One B-rep face of a CAD part: STEP entity #863.
In plain terms, the planar face has unit normal (0, -1, 0).
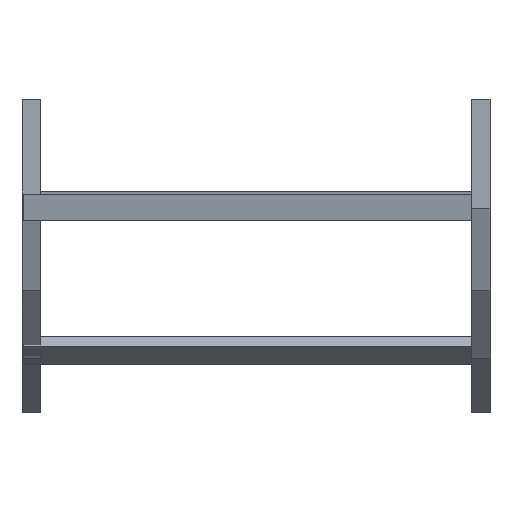
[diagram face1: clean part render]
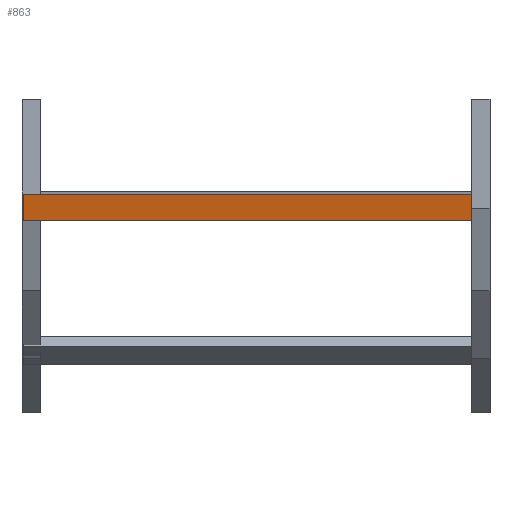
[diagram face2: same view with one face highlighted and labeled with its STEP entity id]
Its self-contained STEP definition (entity closure, numbers rounded to 3 decimals):
#3 = CARTESIAN_POINT ( 'NONE',  ( 348., 0., 20.25 ) ) ;
#14 = EDGE_CURVE ( 'NONE', #1647, #810, #1012, .T. ) ;
#158 = LINE ( 'NONE', #415, #785 ) ;
#229 = VERTEX_POINT ( 'NONE', #1099 ) ;
#249 = PLANE ( 'NONE',  #1543 ) ;
#307 = EDGE_LOOP ( 'NONE', ( #422, #1336, #856, #390 ) ) ;
#362 = VECTOR ( 'NONE', #1411, 1000. ) ;
#377 = EDGE_CURVE ( 'NONE', #810, #803, #158, .T. ) ;
#390 = ORIENTED_EDGE ( 'NONE', *, *, #14, .T. ) ;
#398 = CARTESIAN_POINT ( 'NONE',  ( 348., 0., -20.25 ) ) ;
#415 = CARTESIAN_POINT ( 'NONE',  ( -348., 0., 20.25 ) ) ;
#422 = ORIENTED_EDGE ( 'NONE', *, *, #377, .T. ) ;
#443 = LINE ( 'NONE', #1481, #1237 ) ;
#534 = DIRECTION ( 'NONE',  ( 0., 1., 0. ) ) ;
#535 = EDGE_CURVE ( 'NONE', #1647, #229, #443, .T. ) ;
#639 = LINE ( 'NONE', #398, #362 ) ;
#757 = CARTESIAN_POINT ( 'NONE',  ( 348., 0., 20.25 ) ) ;
#770 = EDGE_CURVE ( 'NONE', #229, #803, #639, .T. ) ;
#785 = VECTOR ( 'NONE', #1434, 1000. ) ;
#803 = VERTEX_POINT ( 'NONE', #1674 ) ;
#810 = VERTEX_POINT ( 'NONE', #1019 ) ;
#856 = ORIENTED_EDGE ( 'NONE', *, *, #535, .F. ) ;
#863 = ADVANCED_FACE ( 'NONE', ( #1418 ), #249, .F. ) ;
#952 = DIRECTION ( 'NONE',  ( 0., 0., -1. ) ) ;
#973 = CARTESIAN_POINT ( 'NONE',  ( 348., 0., 20.25 ) ) ;
#1000 = DIRECTION ( 'NONE',  ( -1., 0., 0. ) ) ;
#1012 = LINE ( 'NONE', #757, #1564 ) ;
#1019 = CARTESIAN_POINT ( 'NONE',  ( -348., 0., 20.25 ) ) ;
#1031 = DIRECTION ( 'NONE',  ( 0., 0., 1. ) ) ;
#1099 = CARTESIAN_POINT ( 'NONE',  ( 348., 0., -20.25 ) ) ;
#1237 = VECTOR ( 'NONE', #952, 1000. ) ;
#1336 = ORIENTED_EDGE ( 'NONE', *, *, #770, .F. ) ;
#1411 = DIRECTION ( 'NONE',  ( -1., 0., 0. ) ) ;
#1418 = FACE_OUTER_BOUND ( 'NONE', #307, .T. ) ;
#1434 = DIRECTION ( 'NONE',  ( 0., 0., -1. ) ) ;
#1481 = CARTESIAN_POINT ( 'NONE',  ( 348., 0., 20.25 ) ) ;
#1543 = AXIS2_PLACEMENT_3D ( 'NONE', #3, #534, #1031 ) ;
#1564 = VECTOR ( 'NONE', #1000, 1000. ) ;
#1647 = VERTEX_POINT ( 'NONE', #973 ) ;
#1674 = CARTESIAN_POINT ( 'NONE',  ( -348., 0., -20.25 ) ) ;
